VERSION 5.7 ;
  NOWIREEXTENSIONATPIN ON ;
  DIVIDERCHAR "/" ;
  BUSBITCHARS "[]" ;
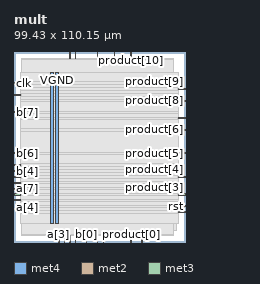
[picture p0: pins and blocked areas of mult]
MACRO mult
  CLASS BLOCK ;
  FOREIGN mult ;
  ORIGIN 0.000 0.000 ;
  SIZE 99.430 BY 110.150 ;
  PIN VGND
    DIRECTION INOUT ;
    USE GROUND ;
    PORT
      LAYER met4 ;
        RECT 24.340 10.640 25.940 98.160 ;
    END
  END VGND
  PIN VPWR
    DIRECTION INOUT ;
    USE POWER ;
    PORT
      LAYER met4 ;
        RECT 21.040 10.640 22.640 98.160 ;
    END
  END VPWR
  PIN a[0]
    DIRECTION INPUT ;
    USE SIGNAL ;
    ANTENNAGATEAREA 0.196500 ;
    PORT
      LAYER met2 ;
        RECT 51.610 0.000 51.890 4.000 ;
    END
  END a[0]
  PIN a[1]
    DIRECTION INPUT ;
    USE SIGNAL ;
    ANTENNAGATEAREA 0.196500 ;
    PORT
      LAYER met2 ;
        RECT 48.390 0.000 48.670 4.000 ;
    END
  END a[1]
  PIN a[2]
    DIRECTION INPUT ;
    USE SIGNAL ;
    ANTENNAGATEAREA 0.196500 ;
    PORT
      LAYER met2 ;
        RECT 35.510 0.000 35.790 4.000 ;
    END
  END a[2]
  PIN a[3]
    DIRECTION INPUT ;
    USE SIGNAL ;
    ANTENNAGATEAREA 0.196500 ;
    PORT
      LAYER met2 ;
        RECT 25.850 0.000 26.130 4.000 ;
    END
  END a[3]
  PIN a[4]
    DIRECTION INPUT ;
    USE SIGNAL ;
    ANTENNAGATEAREA 0.196500 ;
    PORT
      LAYER met3 ;
        RECT 0.000 23.840 4.000 24.440 ;
    END
  END a[4]
  PIN a[5]
    DIRECTION INPUT ;
    USE SIGNAL ;
    ANTENNAGATEAREA 0.196500 ;
    PORT
      LAYER met3 ;
        RECT 0.000 37.440 4.000 38.040 ;
    END
  END a[5]
  PIN a[6]
    DIRECTION INPUT ;
    USE SIGNAL ;
    ANTENNAGATEAREA 0.196500 ;
    PORT
      LAYER met3 ;
        RECT 0.000 34.040 4.000 34.640 ;
    END
  END a[6]
  PIN a[7]
    DIRECTION INPUT ;
    USE SIGNAL ;
    ANTENNAGATEAREA 0.196500 ;
    PORT
      LAYER met3 ;
        RECT 0.000 30.640 4.000 31.240 ;
    END
  END a[7]
  PIN b[0]
    DIRECTION INPUT ;
    USE SIGNAL ;
    ANTENNAGATEAREA 0.196500 ;
    PORT
      LAYER met2 ;
        RECT 41.950 0.000 42.230 4.000 ;
    END
  END b[0]
  PIN b[1]
    DIRECTION INPUT ;
    USE SIGNAL ;
    ANTENNAGATEAREA 0.196500 ;
    PORT
      LAYER met2 ;
        RECT 29.070 0.000 29.350 4.000 ;
    END
  END b[1]
  PIN b[2]
    DIRECTION INPUT ;
    USE SIGNAL ;
    ANTENNAGATEAREA 0.196500 ;
    PORT
      LAYER met2 ;
        RECT 32.290 0.000 32.570 4.000 ;
    END
  END b[2]
  PIN b[3]
    DIRECTION INPUT ;
    USE SIGNAL ;
    ANTENNAGATEAREA 0.196500 ;
    PORT
      LAYER met3 ;
        RECT 0.000 27.240 4.000 27.840 ;
    END
  END b[3]
  PIN b[4]
    DIRECTION INPUT ;
    USE SIGNAL ;
    ANTENNAGATEAREA 0.196500 ;
    PORT
      LAYER met3 ;
        RECT 0.000 40.840 4.000 41.440 ;
    END
  END b[4]
  PIN b[5]
    DIRECTION INPUT ;
    USE SIGNAL ;
    ANTENNAGATEAREA 0.196500 ;
    PORT
      LAYER met3 ;
        RECT 0.000 44.240 4.000 44.840 ;
    END
  END b[5]
  PIN b[6]
    DIRECTION INPUT ;
    USE SIGNAL ;
    ANTENNAGATEAREA 0.196500 ;
    PORT
      LAYER met3 ;
        RECT 0.000 51.040 4.000 51.640 ;
    END
  END b[6]
  PIN b[7]
    DIRECTION INPUT ;
    USE SIGNAL ;
    ANTENNAGATEAREA 0.196500 ;
    PORT
      LAYER met3 ;
        RECT 0.000 74.840 4.000 75.440 ;
    END
  END b[7]
  PIN clk
    DIRECTION INPUT ;
    USE SIGNAL ;
    ANTENNAGATEAREA 0.852000 ;
    PORT
      LAYER met3 ;
        RECT 0.000 91.840 4.000 92.440 ;
    END
  END clk
  PIN product[0]
    DIRECTION OUTPUT ;
    USE SIGNAL ;
    ANTENNADIFFAREA 0.445500 ;
    PORT
      LAYER met2 ;
        RECT 67.710 0.000 67.990 4.000 ;
    END
  END product[0]
  PIN product[10]
    DIRECTION OUTPUT ;
    USE SIGNAL ;
    ANTENNADIFFAREA 0.445500 ;
    PORT
      LAYER met2 ;
        RECT 67.710 106.150 67.990 110.150 ;
    END
  END product[10]
  PIN product[11]
    DIRECTION OUTPUT ;
    USE SIGNAL ;
    ANTENNADIFFAREA 0.445500 ;
    PORT
      LAYER met2 ;
        RECT 58.050 106.150 58.330 110.150 ;
    END
  END product[11]
  PIN product[12]
    DIRECTION OUTPUT ;
    USE SIGNAL ;
    ANTENNADIFFAREA 0.445500 ;
    PORT
      LAYER met2 ;
        RECT 48.390 106.150 48.670 110.150 ;
    END
  END product[12]
  PIN product[13]
    DIRECTION OUTPUT ;
    USE SIGNAL ;
    ANTENNADIFFAREA 0.445500 ;
    PORT
      LAYER met2 ;
        RECT 35.510 106.150 35.790 110.150 ;
    END
  END product[13]
  PIN product[14]
    DIRECTION OUTPUT ;
    USE SIGNAL ;
    ANTENNADIFFAREA 0.445500 ;
    PORT
      LAYER met2 ;
        RECT 32.290 106.150 32.570 110.150 ;
    END
  END product[14]
  PIN product[15]
    DIRECTION OUTPUT ;
    USE SIGNAL ;
    ANTENNADIFFAREA 0.445500 ;
    PORT
      LAYER met3 ;
        RECT 0.000 85.040 4.000 85.640 ;
    END
  END product[15]
  PIN product[1]
    DIRECTION OUTPUT ;
    USE SIGNAL ;
    ANTENNADIFFAREA 0.445500 ;
    PORT
      LAYER met2 ;
        RECT 74.150 0.000 74.430 4.000 ;
    END
  END product[1]
  PIN product[2]
    DIRECTION OUTPUT ;
    USE SIGNAL ;
    ANTENNADIFFAREA 0.445500 ;
    PORT
      LAYER met3 ;
        RECT 95.430 17.040 99.430 17.640 ;
    END
  END product[2]
  PIN product[3]
    DIRECTION OUTPUT ;
    USE SIGNAL ;
    ANTENNADIFFAREA 0.445500 ;
    PORT
      LAYER met3 ;
        RECT 95.430 27.240 99.430 27.840 ;
    END
  END product[3]
  PIN product[4]
    DIRECTION OUTPUT ;
    USE SIGNAL ;
    ANTENNADIFFAREA 0.445500 ;
    PORT
      LAYER met3 ;
        RECT 95.430 37.440 99.430 38.040 ;
    END
  END product[4]
  PIN product[5]
    DIRECTION OUTPUT ;
    USE SIGNAL ;
    ANTENNADIFFAREA 0.445500 ;
    PORT
      LAYER met3 ;
        RECT 95.430 51.040 99.430 51.640 ;
    END
  END product[5]
  PIN product[6]
    DIRECTION OUTPUT ;
    USE SIGNAL ;
    ANTENNADIFFAREA 0.445500 ;
    PORT
      LAYER met3 ;
        RECT 95.430 64.640 99.430 65.240 ;
    END
  END product[6]
  PIN product[7]
    DIRECTION OUTPUT ;
    USE SIGNAL ;
    ANTENNADIFFAREA 0.445500 ;
    PORT
      LAYER met3 ;
        RECT 95.430 71.440 99.430 72.040 ;
    END
  END product[7]
  PIN product[8]
    DIRECTION OUTPUT ;
    USE SIGNAL ;
    ANTENNADIFFAREA 0.445500 ;
    PORT
      LAYER met3 ;
        RECT 95.430 81.640 99.430 82.240 ;
    END
  END product[8]
  PIN product[9]
    DIRECTION OUTPUT ;
    USE SIGNAL ;
    ANTENNADIFFAREA 0.445500 ;
    PORT
      LAYER met3 ;
        RECT 95.430 88.440 99.430 89.040 ;
    END
  END product[9]
  PIN rst
    DIRECTION INPUT ;
    USE SIGNAL ;
    ANTENNAGATEAREA 0.196500 ;
    PORT
      LAYER met3 ;
        RECT 95.430 20.440 99.430 21.040 ;
    END
  END rst
  OBS
      LAYER nwell ;
        RECT 5.330 10.795 94.030 98.005 ;
      LAYER li1 ;
        RECT 5.520 10.795 93.840 98.005 ;
      LAYER met1 ;
        RECT 4.210 6.840 94.140 98.160 ;
      LAYER met2 ;
        RECT 4.230 105.870 32.010 106.150 ;
        RECT 32.850 105.870 35.230 106.150 ;
        RECT 36.070 105.870 48.110 106.150 ;
        RECT 48.950 105.870 57.770 106.150 ;
        RECT 58.610 105.870 67.430 106.150 ;
        RECT 68.270 105.870 92.370 106.150 ;
        RECT 4.230 4.280 92.370 105.870 ;
        RECT 4.230 4.000 25.570 4.280 ;
        RECT 26.410 4.000 28.790 4.280 ;
        RECT 29.630 4.000 32.010 4.280 ;
        RECT 32.850 4.000 35.230 4.280 ;
        RECT 36.070 4.000 41.670 4.280 ;
        RECT 42.510 4.000 48.110 4.280 ;
        RECT 48.950 4.000 51.330 4.280 ;
        RECT 52.170 4.000 67.430 4.280 ;
        RECT 68.270 4.000 73.870 4.280 ;
        RECT 74.710 4.000 92.370 4.280 ;
      LAYER met3 ;
        RECT 3.990 92.840 95.430 98.085 ;
        RECT 4.400 91.440 95.430 92.840 ;
        RECT 3.990 89.440 95.430 91.440 ;
        RECT 3.990 88.040 95.030 89.440 ;
        RECT 3.990 86.040 95.430 88.040 ;
        RECT 4.400 84.640 95.430 86.040 ;
        RECT 3.990 82.640 95.430 84.640 ;
        RECT 3.990 81.240 95.030 82.640 ;
        RECT 3.990 75.840 95.430 81.240 ;
        RECT 4.400 74.440 95.430 75.840 ;
        RECT 3.990 72.440 95.430 74.440 ;
        RECT 3.990 71.040 95.030 72.440 ;
        RECT 3.990 65.640 95.430 71.040 ;
        RECT 3.990 64.240 95.030 65.640 ;
        RECT 3.990 52.040 95.430 64.240 ;
        RECT 4.400 50.640 95.030 52.040 ;
        RECT 3.990 45.240 95.430 50.640 ;
        RECT 4.400 43.840 95.430 45.240 ;
        RECT 3.990 41.840 95.430 43.840 ;
        RECT 4.400 40.440 95.430 41.840 ;
        RECT 3.990 38.440 95.430 40.440 ;
        RECT 4.400 37.040 95.030 38.440 ;
        RECT 3.990 35.040 95.430 37.040 ;
        RECT 4.400 33.640 95.430 35.040 ;
        RECT 3.990 31.640 95.430 33.640 ;
        RECT 4.400 30.240 95.430 31.640 ;
        RECT 3.990 28.240 95.430 30.240 ;
        RECT 4.400 26.840 95.030 28.240 ;
        RECT 3.990 24.840 95.430 26.840 ;
        RECT 4.400 23.440 95.430 24.840 ;
        RECT 3.990 21.440 95.430 23.440 ;
        RECT 3.990 20.040 95.030 21.440 ;
        RECT 3.990 18.040 95.430 20.040 ;
        RECT 3.990 16.640 95.030 18.040 ;
        RECT 3.990 10.715 95.430 16.640 ;
  END
END mult
END LIBRARY

